# A block with no timing model, its clock taken in by an input pin, an
# inout pin and a pin without shapes, read after clock.lef for the clock
# tree synthesis tests.
VERSION 5.8 ;
BUSBITCHARS "[]" ;
DIVIDERCHAR "/" ;

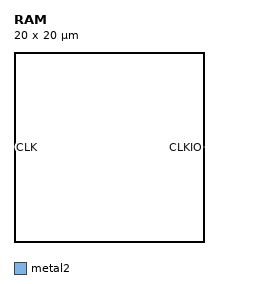
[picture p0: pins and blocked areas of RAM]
MACRO RAM
  CLASS BLOCK ;
  ORIGIN 0 0 ;
  SIZE 20 BY 20 ;
  PIN CLK
    DIRECTION INPUT ;
    USE CLOCK ;
    PORT
      LAYER metal2 ;
        RECT 0 9.9 0.2 10.1 ;
    END
  END CLK
  PIN CLKIO
    DIRECTION INOUT ;
    USE CLOCK ;
    PORT
      LAYER metal2 ;
        RECT 19.8 9.9 20 10.1 ;
    END
  END CLKIO
  PIN CLKBARE
    DIRECTION INPUT ;
    USE CLOCK ;
  END CLKBARE
END RAM
END LIBRARY
